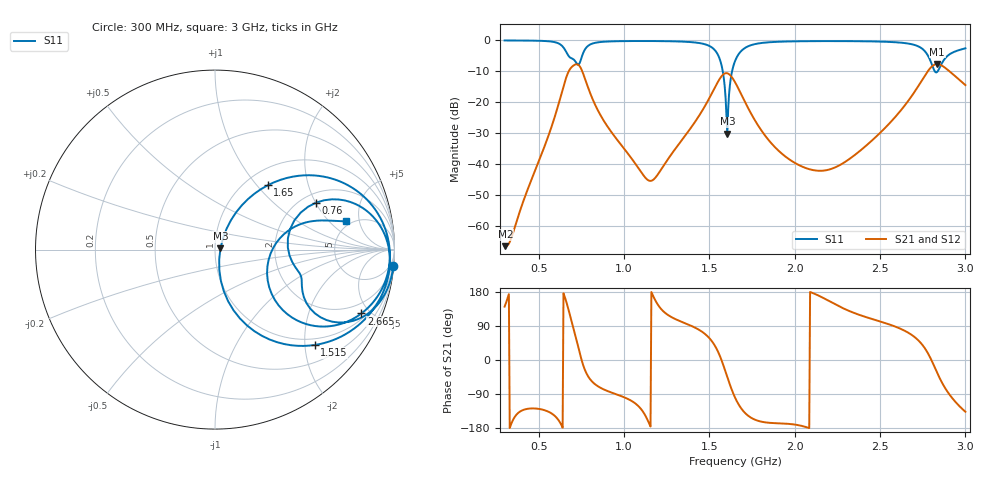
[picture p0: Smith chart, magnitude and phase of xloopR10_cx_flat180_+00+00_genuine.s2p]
! xloopR10_cx_flat180_+00+00_genuine, gap C 0.80 pF
! simulated by sim/fixtures_fdtd.py (S12 = S21, S22 not computed)
# HZ S RI R 50
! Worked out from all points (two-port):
!   541 points, 300 MHz to 3 GHz, reference 50 ohm
!   highest |S21| = -7.64 dB at 2.835 GHz (marker M1); lowest = -66.5 dB at 305 MHz (marker M2)
!   |S21| within 3 dB of the highest: 670.2 MHz to 759.7 MHz (89.48 MHz wide, 12.5 % of centre); 2.771 GHz to 2.921 GHz (149.5 MHz wide, 5.25 % of centre) (the widest 2 of 3)
!   lowest |S11| = -30.2 dB at 1.605 GHz (marker M3), VSWR 1.06, Z = 53.1 + j0.66 ohm
!   |S11| at or under -10 dB: 1.578 GHz to 1.633 GHz (54.57 MHz wide, 3.4 % of centre); 2.821 GHz to 2.837 GHz (16.01 MHz wide, 0.566 % of centre)
!   |S22| runs from - to - dB; largest |S21 - S12| = 0
!   S11 on the Smith chart (normalised r, x): 300 MHz: 0, -21; 760 MHz: 2.37, +2.02; 1.515 GHz: 0.85, -2.21; 1.65 GHz: 1.25, +1.14; 2.665 GHz: 1.30, -4.43; 3 GHz: 4.53, +3.19
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3e8  0.994 -0.0936  -0.000372 0.000303  -0.000372 0.000303  0 0
3.05e8  0.9937 -0.0955  -0.000398 0.000261  -0.000398 0.000261  0 0
5.55e8  0.9308 -0.2739  -0.0201 -0.0194  -0.0201 -0.0194  0 0
6.4e8  0.6873 -0.4062  -0.1614 -0.004  -0.1614 -0.004  0 0
7.05e8  0.4723 -0.1332  0.0601 0.3916  0.0601 0.3916  0 0
7.5e8  0.4773 0.2059  0.3414 0.0111  0.3414 0.0111  0 0
7.6e8  0.5638 0.2618  0.2846 -0.0667  0.2846 -0.0667  0 0
8.45e8  0.9201 0.1322  0.0273 -0.0705  0.0273 -0.0705  0 0
1.11e9  0.9717 -0.1094  -0.00491 -0.00476  -0.00491 -0.00476  0 0
1.2e9  0.9609 -0.1671  -0.0057 0.00405  -0.0057 0.00405  0 0
1.515e9  0.5544 -0.5316  0.0917 0.1067  0.0917 0.1067  0 0
1.57e9  0.139 -0.3836  0.2615 0.0036  0.2615 0.0036  0 0
1.605e9  0.0304 0.0062  0.207 -0.2096  0.207 -0.2096  0 0
1.65e9  0.2926 0.3578  -0.0329 -0.2094  -0.0329 -0.2094  0 0
1.785e9  0.8473 0.2779  -0.04 -0.0142  -0.04 -0.0142  0 0
2.1e9  0.9732 -0.00334  -0.00812 0.000321  -0.00812 0.000321  0 0
2.275e9  0.9703 -0.0905  -0.00754 0.0067  -0.00754 0.0067  0 0
2.55e9  0.9137 -0.248  -0.00345 0.0441  -0.00345 0.0441  0 0
2.665e9  0.8156 -0.3558  0.0325 0.1004  0.0325 0.1004  0 0
2.77e9  0.4827 -0.406  0.2612 0.1259  0.2612 0.1259  0 0
2.835e9  0.3094 -0.0229  0.3437 -0.2327  0.3437 -0.2327  0 0
3e9  0.7287 0.1568  -0.138 -0.1306  -0.138 -0.1306  0 0
